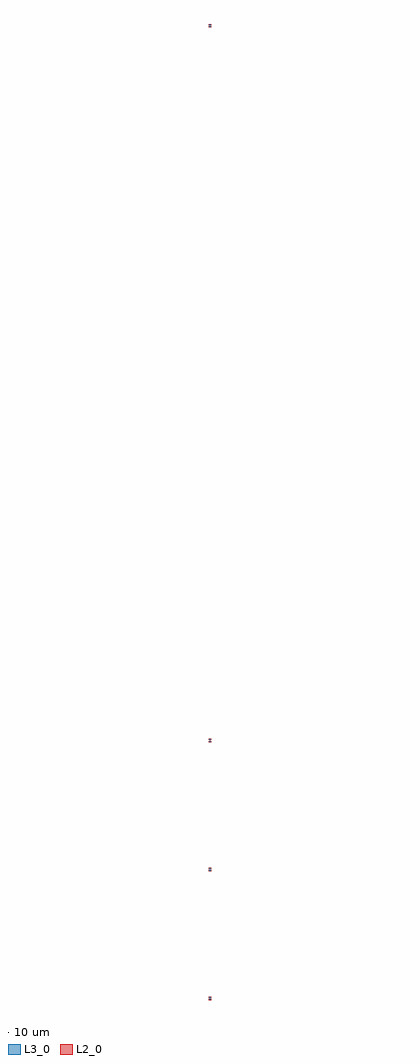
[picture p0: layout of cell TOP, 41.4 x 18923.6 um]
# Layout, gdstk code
import gdstk
lib = gdstk.Library(unit=1e-6, precision=1e-09)
def P(c, l, *ps):  # polygons
    for p in ps: c.add(gdstk.Polygon(p, *l))
L2_0 = (2, 0)
L3_0 = (3, 0)

q19gap = lib.new_cell('Q19GAP')
P(q19gap, L2_0, [(779.3,2253.3),(779.3,2274),(798.905,2284),(799.405,2284),(799.405,2286),(799.605,2286),(799.605,2284),(780,2274),(780,2254),(820,2254),(820,2274),(800.395,2284),(800.395,2286),(797.3,2286),(797.3,2286.2),(796.8,2286.2),(779.3,2296.2),(779.3,2316.2),(780,2316.2),(780,2296.2),(797.5,2286.2),(802.5,2286.2),(820,2296.2),(820,2316.2),(779.3,2316.2),(779.3,2316.9),(820.7,2316.9),(820.7,2296.2),(803.2,2286.2),(802.7,2286.2),(802.7,2286),(800.595,2286),(800.595,2284),(801.095,2284),(820.7,2274),(820.7,2253.3)],
  [(779.3,4753.3),(779.3,4774),(798.905,4784),(799.405,4784),(799.405,4786),(799.605,4786),(799.605,4784),(780,4774),(780,4754),(820,4754),(820,4774),(800.395,4784),(800.395,4786),(797.3,4786),(797.3,4786.2),(796.8,4786.2),(779.3,4796.2),(779.3,4816.2),(780,4816.2),(780,4796.2),(797.5,4786.2),(802.5,4786.2),(820,4796.2),(820,4816.2),(779.3,4816.2),(779.3,4816.9),(820.7,4816.9),(820.7,4796.2),(803.2,4786.2),(802.7,4786.2),(802.7,4786),(800.595,4786),(800.595,4784),(801.095,4784),(820.7,4774),(820.7,4753.3)],
  [(779.3,7253.3),(779.3,7274),(798.905,7284),(799.405,7284),(799.405,7286),(799.605,7286),(799.605,7284),(780,7274),(780,7254),(820,7254),(820,7274),(800.395,7284),(800.395,7286),(797.3,7286),(797.3,7286.2),(796.8,7286.2),(779.3,7296.2),(779.3,7316.2),(780,7316.2),(780,7296.2),(797.5,7286.2),(802.5,7286.2),(820,7296.2),(820,7316.2),(779.3,7316.2),(779.3,7316.9),(820.7,7316.9),(820.7,7296.2),(803.2,7286.2),(802.7,7286.2),(802.7,7286),(800.595,7286),(800.595,7284),(801.095,7284),(820.7,7274),(820.7,7253.3)],
  [(779.3,21113.3),(779.3,21134),(798.905,21144),(799.405,21144),(799.405,21146),(799.605,21146),(799.605,21144),(780,21134),(780,21114),(820,21114),(820,21134),(800.395,21144),(800.395,21146),(797.3,21146),(797.3,21146.2),(796.8,21146.2),(779.3,21156.2),(779.3,21176.2),(780,21176.2),(780,21156.2),(797.5,21146.2),(802.5,21146.2),(820,21156.2),(820,21176.2),(779.3,21176.2),(779.3,21176.9),(820.7,21176.9),(820.7,21156.2),(803.2,21146.2),(802.7,21146.2),(802.7,21146),(800.595,21146),(800.595,21144),(801.095,21144),(820.7,21134),(820.7,21113.3)])

q19pin = lib.new_cell('Q19PIN')
P(q19pin, L3_0, [(780,2254),(780,2274),(799.605,2284),(799.605,2286),(800.395,2286),(800.395,2284),(820,2274),(820,2254)],
  [(797.5,2286.2),(780,2296.2),(780,2316.2),(820,2316.2),(820,2296.2),(802.5,2286.2)],
  [(780,4754),(780,4774),(799.605,4784),(799.605,4786),(800.395,4786),(800.395,4784),(820,4774),(820,4754)],
  [(797.5,4786.2),(780,4796.2),(780,4816.2),(820,4816.2),(820,4796.2),(802.5,4786.2)],
  [(780,7254),(780,7274),(799.605,7284),(799.605,7286),(800.395,7286),(800.395,7284),(820,7274),(820,7254)],
  [(797.5,7286.2),(780,7296.2),(780,7316.2),(820,7316.2),(820,7296.2),(802.5,7286.2)],
  [(780,21114),(780,21134),(799.605,21144),(799.605,21146),(800.395,21146),(800.395,21144),(820,21134),(820,21114)],
  [(797.5,21146.2),(780,21156.2),(780,21176.2),(820,21176.2),(820,21156.2),(802.5,21146.2)])

q19 = lib.new_cell('Q19')

top = lib.new_cell('TOP')
top.add(gdstk.Reference(q19gap, (0,0)))
top.add(gdstk.Reference(q19pin, (0,0)))
top.add(gdstk.Reference(q19, (0,0)))

lib.write_gds('TOP.gds')
